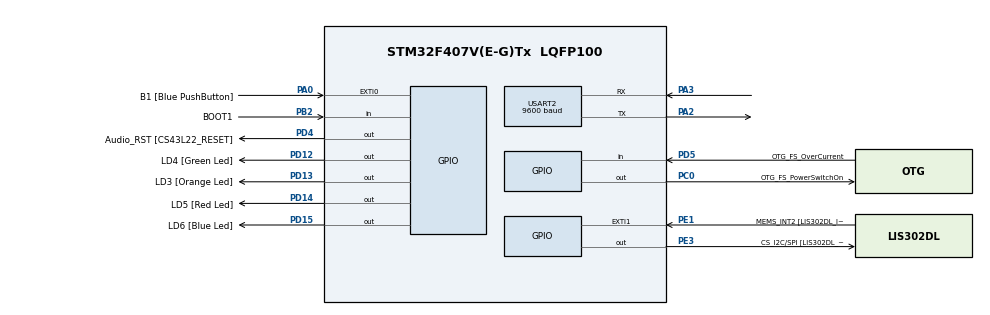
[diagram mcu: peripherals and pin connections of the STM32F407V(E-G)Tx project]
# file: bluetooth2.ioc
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Dma.Request0=USART2_RX
Dma.USART2_RX.0.Direction=DMA_PERIPH_TO_MEMORY
Dma.USART2_RX.0.FIFOMode=DMA_FIFOMODE_DISABLE
Dma.USART2_RX.0.Instance=DMA1_Stream5
Dma.USART2_RX.0.MemDataAlignment=DMA_MDATAALIGN_BYTE
Dma.USART2_RX.0.MemInc=DMA_MINC_ENABLE
Dma.USART2_RX.0.Mode=DMA_NORMAL
Dma.USART2_RX.0.PeriphDataAlignment=DMA_PDATAALIGN_BYTE
Dma.USART2_RX.0.PeriphInc=DMA_PINC_DISABLE
Dma.USART2_RX.0.Priority=DMA_PRIORITY_LOW
Mcu.Family=STM32F4
Mcu.Name=STM32F407V(E-G)Tx
Mcu.Package=LQFP100
NVIC.DMA1_Stream5_IRQn=true\:0\:0\:false\:false\:true\:false\:true
NVIC.PriorityGroup=NVIC_PRIORITYGROUP_0
PA0-WKUP.GPIO_Label=B1 [Blue PushButton]
PA0-WKUP.Signal=GPXTI0
PA10.GPIO_Label=OTG_FS_ID
PA10.GPIO_Mode=GPIO_MODE_AF_PP
PA10.GPIO_PuPd=GPIO_NOPULL
PA10.GPIO_Speed=GPIO_SPEED_FREQ_LOW
PA10.Signal=USB_OTG_FS_ID
PA11.GPIO_Label=OTG_FS_DM
PA11.GPIO_Mode=GPIO_MODE_AF_PP
PA11.GPIO_PuPd=GPIO_NOPULL
PA11.GPIO_Speed=GPIO_SPEED_FREQ_LOW
PA11.Signal=USB_OTG_FS_DM
PA12.GPIO_Label=OTG_FS_DP
PA12.GPIO_Mode=GPIO_MODE_AF_PP
PA12.GPIO_PuPd=GPIO_NOPULL
PA12.GPIO_Speed=GPIO_SPEED_FREQ_LOW
PA12.Signal=USB_OTG_FS_DP
PA13.GPIO_Label=SWDIO
PA13.Signal=SYS_JTMS-SWDIO
PA14.GPIO_Label=SWCLK
PA14.Signal=SYS_JTCK-SWCLK
PA2.Mode=Asynchronous
PA2.Signal=USART2_TX
PA3.Mode=Asynchronous
PA3.Signal=USART2_RX
PA4.GPIO_Label=I2S3_WS [CS43L22_LRCK]
PA4.GPIO_Mode=GPIO_MODE_AF_PP
PA4.GPIO_PuPd=GPIO_NOPULL
PA4.GPIO_Speed=GPIO_SPEED_FREQ_LOW
PA4.Signal=I2S3_WS
PA5.GPIO_Label=SPI1_SCK [LIS302DL_SCL/SPC]
PA5.GPIO_Mode=GPIO_MODE_AF_PP
PA5.GPIO_PuPd=GPIO_NOPULL
PA5.GPIO_Speed=GPIO_SPEED_FREQ_LOW
PA5.Signal=SPI1_SCK
PA6.GPIO_Label=SPI1_MISO [LIS302DL_SDO]
PA6.GPIO_Mode=GPIO_MODE_AF_PP
PA6.GPIO_PuPd=GPIO_NOPULL
PA6.GPIO_Speed=GPIO_SPEED_FREQ_LOW
PA6.Signal=SPI1_MISO
PA7.GPIO_Label=SPI1_MOSI [LIS302DL_SDA/SDI/SDO]
PA7.GPIO_Mode=GPIO_MODE_AF_PP
PA7.GPIO_PuPd=GPIO_NOPULL
PA7.GPIO_Speed=GPIO_SPEED_FREQ_LOW
PA7.Signal=SPI1_MOSI
PA9.GPIO_Label=VBUS_FS
PA9.GPIO_Mode=GPIO_MODE_INPUT
PA9.GPIO_PuPd=GPIO_NOPULL
PA9.Signal=USB_OTG_FS_VBUS
PB10.GPIO_Label=CLK_IN [MP45DT02_CLK]
PB10.GPIO_Mode=GPIO_MODE_AF_PP
PB10.GPIO_PuPd=GPIO_NOPULL
PB10.GPIO_Speed=GPIO_SPEED_FREQ_LOW
PB10.Signal=I2S2_CK
PB2.GPIO_Label=BOOT1
PB2.GPIO_Mode=GPIO_MODE_INPUT
PB2.GPIO_PuPd=GPIO_NOPULL
PB2.Signal=GPIO_Input
PB3.GPIO_Label=SWO
PB3.Signal=SYS_JTDO-SWO
PB6.GPIO_Label=Audio_SCL [CS43L22_SCL]
PB6.GPIO_Mode=GPIO_MODE_AF_OD
PB6.GPIO_PuPd=GPIO_NOPULL
PB6.GPIO_Speed=GPIO_SPEED_FREQ_LOW
PB6.Signal=I2C1_SCL
PB9.GPIO_Label=Audio_SDA [CS43L22_SDA]
PB9.GPIO_Mode=GPIO_MODE_AF_OD
PB9.GPIO_PuPd=GPIO_NOPULL
PB9.GPIO_Speed=GPIO_SPEED_FREQ_LOW
PB9.Signal=I2C1_SDA
PC0.GPIO_Label=OTG_FS_PowerSwitchOn
PC0.GPIO_PuPd=GPIO_NOPULL
PC0.GPIO_Speed=GPIO_SPEED_FREQ_LOW
PC0.PinState=GPIO_PIN_SET
PC0.Signal=GPIO_Output
PC10.GPIO_Label=I2S3_SCK [CS43L22_SCLK]
PC10.GPIO_Mode=GPIO_MODE_AF_PP
PC10.GPIO_PuPd=GPIO_NOPULL
PC10.GPIO_Speed=GPIO_SPEED_FREQ_LOW
PC10.Signal=I2S3_CK
PC12.GPIO_Label=I2S3_SD [CS43L22_SDIN]
PC12.GPIO_Mode=GPIO_MODE_AF_PP
PC12.GPIO_PuPd=GPIO_NOPULL
PC12.GPIO_Speed=GPIO_SPEED_FREQ_LOW
PC12.Signal=I2S3_SD
PC14-OSC32_IN.GPIO_Label=PC14-OSC32_IN
PC14-OSC32_IN.Signal=RCC_OSC32_IN
PC15-OSC32_OUT.GPIO_Label=PC15-OSC32_OUT
PC15-OSC32_OUT.Signal=RCC_OSC32_OUT
PC3.GPIO_Label=PDM_OUT [MP45DT02_DOUT]
PC3.GPIO_Mode=GPIO_MODE_AF_PP
PC3.GPIO_PuPd=GPIO_NOPULL
PC3.GPIO_Speed=GPIO_SPEED_FREQ_LOW
PC3.Signal=I2S2_SD
PC7.GPIO_Label=I2S3_MCK [CS43L22_MCLK]
PC7.GPIO_Mode=GPIO_MODE_AF_PP
PC7.GPIO_PuPd=GPIO_NOPULL
PC7.GPIO_Speed=GPIO_SPEED_FREQ_LOW
PC7.Signal=I2S3_MCK
PD12.GPIO_Label=LD4 [Green Led]
PD12.GPIO_PuPd=GPIO_NOPULL
PD12.GPIO_Speed=GPIO_SPEED_FREQ_LOW
PD12.Signal=GPIO_Output
PD13.GPIO_Label=LD3 [Orange Led]
PD13.GPIO_PuPd=GPIO_NOPULL
PD13.GPIO_Speed=GPIO_SPEED_FREQ_LOW
PD13.Signal=GPIO_Output
PD14.GPIO_Label=LD5 [Red Led]
PD14.GPIO_PuPd=GPIO_NOPULL
PD14.GPIO_Speed=GPIO_SPEED_FREQ_LOW
PD14.Signal=GPIO_Output
PD15.GPIO_Label=LD6 [Blue Led]
PD15.GPIO_PuPd=GPIO_NOPULL
PD15.GPIO_Speed=GPIO_SPEED_FREQ_LOW
PD15.Signal=GPIO_Output
PD4.GPIO_Label=Audio_RST [CS43L22_RESET]
PD4.GPIO_PuPd=GPIO_NOPULL
PD4.GPIO_Speed=GPIO_SPEED_FREQ_LOW
PD4.Signal=GPIO_Output
PD5.GPIO_Label=OTG_FS_OverCurrent
PD5.GPIO_Mode=GPIO_MODE_INPUT
PD5.GPIO_PuPd=GPIO_NOPULL
PD5.Signal=GPIO_Input
PE1.GPIO_Label=MEMS_INT2 [LIS302DL_INT2]
PE1.GPIO_ModeDefaultEXTI=GPIO_MODE_EVT_RISING
PE1.GPIO_PuPd=GPIO_NOPULL
PE1.Signal=GPXTI1
PE3.GPIO_Label=CS_I2C/SPI [LIS302DL_CS_I2C/SPI]
PE3.GPIO_PuPd=GPIO_NOPULL
PE3.GPIO_Speed=GPIO_SPEED_FREQ_LOW
PE3.Signal=GPIO_Output
PH0-OSC_IN.GPIO_Label=PH0-OSC_IN
PH0-OSC_IN.Signal=RCC_OSC_IN
PH1-OSC_OUT.GPIO_Label=PH1-OSC_OUT
PH1-OSC_OUT.Signal=RCC_OSC_OUT
ProjectManager.HeapSize=0x200
ProjectManager.StackSize=0x400
ProjectManager.TargetToolchain=Makefile
RCC.48MHZClocksFreq_Value=14285714.285714285
RCC.AHBFreq_Value=25000000
RCC.APB1CLKDivider=RCC_HCLK_DIV4
RCC.APB1Freq_Value=6250000
RCC.APB1TimFreq_Value=12500000
RCC.APB2CLKDivider=RCC_HCLK_DIV2
RCC.APB2Freq_Value=12500000
RCC.APB2TimFreq_Value=25000000
RCC.CortexFreq_Value=25000000
RCC.HCLKFreq_Value=25000000
RCC.HSE_VALUE=8000000
RCC.HSI_VALUE=16000000
RCC.LSE_VALUE=32768
RCC.PLLM=8
RCC.PLLN=50
RCC.PLLP=RCC_PLLP_DIV4
RCC.PLLQ=7
RCC.SYSCLKFreq_VALUE=25000000
RCC.SYSCLKSource=RCC_SYSCLKSOURCE_PLLCLK
RCC.VCOOutputFreq_Value=100000000
USART2.BaudRate=9600
USART2.VirtualMode=VM_ASYNC
board=STM32F407G-DISC1

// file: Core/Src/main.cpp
/* USER CODE BEGIN Header */
/**
  ******************************************************************************
  * @file           : main.c
  * @brief          : Main program body
  ******************************************************************************
  * @attention
  *
  * <h2><center>&copy; Copyright (c) 2021 STMicroelectronics.
  * All rights reserved.</center></h2>
  *
  * This software component is licensed by ST under BSD 3-Clause license,
  * the "License"; You may not use this file except in compliance with the
  * License. You may obtain a copy of the License at:
  *                        opensource.org/licenses/BSD-3-Clause
  *
  ******************************************************************************
  */
/* USER CODE END Header */
#include "main.h"

/* USER CODE BEGIN Includes */
#include <string.h>
#include <stdio.h>
#include <stdlib.h>

//Ben
#include "decisiontree.cpp"
#include <iostream>
#include <vector>
#include <string>
#include <cstring>
#include <fstream>
#include <cmath>
#include <map>
#include <algorithm>
using namespace std;

/* USER CODE END Includes */

UART_HandleTypeDef huart2;
DMA_HandleTypeDef hdma_usart2_rx;

//uint8_t buffer_rx[100];
char buffer_rx[100];

void SystemClock_Config(void);
static void MX_GPIO_Init(void);
static void MX_DMA_Init(void);
static void MX_USART2_UART_Init(void);

/* USER CODE BEGIN 0 */

void HAL_UART_RxCpltCallback(UART_HandleTypeDef *huart){

}

/* USER CODE END 0 */

  int send (char * txData){
  //
  int bytesToSend =10+strlen(txData);
  char send[10000];

  send[0]='#';

  //length of payload
  // Todo: maybe overflow an Bytes
  char msglen [11];
  sprintf(msglen,"%d",strlen(txData));

  int i =1;
  while (i<(strlen(msglen)+1)){
  send[i]=msglen[i-1];
  i=i+1;
  }
  send[i]='|';
  i=i+1;
  int sendi=0;
  while(sendi<strlen(txData)){
  send[i] = txData[sendi];
  i=i+1;
  sendi=sendi+1;
  }

  //Union length of payload and payload, send it
  //strcat (send, txData);

  HAL_UART_Transmit(&huart2, (uint8_t *)  send, strlen(send),400);
  return 1;

  }

  void receievCPP(char * arg){
  	char txData[100];
      while (1){
    	HAL_UART_Receive(&huart2,(uint8_t *) buffer_rx,1,1000);
    	if (buffer_rx[0]== (uint8_t) '#')
    		{
    		break;
    		}

    	}

    	//check for payload length
    	int j=0;
    	char msglen [8];
    	while (1){
    	HAL_UART_Receive(&huart2,(uint8_t *) buffer_rx,1,1000);
    	if (buffer_rx[0]== (uint8_t) '|')
    		{
    		break;
    		}
    	msglen[j]=buffer_rx[0];
    	j= j+1;
    	}

    	int msglength=0;
    	sscanf (msglen, "%d", &msglength);

    	//receive payload
    	HAL_UART_Receive(&huart2,(uint8_t *) buffer_rx,msglength,1000);

    	 int i =0;
    	while (i<msglength){
    	txData[i]= (uint8_t) buffer_rx[i];
    	//buffer_rx[i]=NULL;
    	i=i+1;
    	}

      	strcpy( arg,buffer_rx);
      }

  int receiev (char * txData){
  while (1){
	HAL_UART_Receive(&huart2,(uint8_t *) buffer_rx,1,1000);
	if (buffer_rx[0]== (uint8_t) '#')
		{
		break;
		}

	}

	//check for payload length
	int j=0;
	char msglen [8];
	while (1){
	HAL_UART_Receive(&huart2,(uint8_t *) buffer_rx,1,1000);
	if (buffer_rx[0]== (uint8_t) '|')
		{
		break;
		}
	msglen[j]=buffer_rx[0];
	j= j+1;
	}

	int msglength=0;
	sscanf (msglen, "%d", &msglength);

	//receive payload
	HAL_UART_Receive(&huart2,(uint8_t *) buffer_rx,msglength,1000);

	 int i =0;
	while (i<msglength){
	txData[i]=buffer_rx[i];
	buffer_rx[i]=NULL;
	i=i+1;
	}

  	return 1;
  }

  //Ben

/*  void SplitStringH(char* s, vector<char*> &v){

   	char* temp = "";
   	for(int i=0;i<strlen(s);++i){

   		if(s[i]=='#'){
   			v.push_back(temp);
   			temp = "";
   		}
   		else{
   			temp.push_back(s[i]);
   		}

   	}
   	v.push_back(temp);

   }

   void SplitStringD(char* s, vector<char*> &v){

     	char* temp = "";
     	for(int i=0;i<s.length();++i){

     		if(s[i]=='$'){
     			v.push_back(temp);
     			temp = "";
     		}
     		else{
     			temp.push_back(s[i]);
     		}

     	}
     	v.push_back(temp);

     }

   void SplitStringS(char* s, vector<char*> &v){

     	char* temp = "";
     	for(int i=0;i<s.length();++i){

     		if(s[i]=='/'){
     			v.push_back(temp);
     			temp = "";
     		}
     		else{
     			temp.push_back(s[i]);
     		}

     	}
     	v.push_back(temp);

     }*/

/*  Table StringToTable(char * s1){
 	  vector<string> input;

 	  //may be different depending on libraries
 	  //string slashString = str(s1);
 	  char* slashString(s1);

 	  SplitStringS(slashString,input);

 	  string attrName = input[0];
 	  string data = input[1];
 	  string attrValueList = input[2];

 	 vector<string> attrNamefinal;
 	 SplitStringH(attrName,attrNamefinal);

 	 vector<string> datafinal;
 	 SplitStringD(data,datafinal);

 	 vector<vector<string>> datafinalfinal;
 	 for(int i = 0; i< datafinal.size();i++){
 		 SplitStringH(datafinal[i],datafinalfinal[i]);
 	 }

 	 vector<string> attrValueListfinal;
 	 	 SplitStringD(attrValueList,attrValueListfinal);

 	 vector<vector<string>> attrValueListfinalfinal;
 	 for(int i = 0; i< attrValueListfinal.size();i++){
 	 	 SplitStringH(attrValueListfinal[i],attrValueListfinalfinal[i]);
 	 }

 	 Table tf;
 	       tf.attrName=attrNamefinal;
 	       tf.data=datafinalfinal;
 	       tf.attrValueList=attrValueListfinalfinal;

 	 return tf;
   }*/

  //Ben
  //Test kommentar

    void TableToString(Table t1, char * tableString){
 	  char attrName[1000]  = {};
 	  char data [1000] = {};
 	  char attrValueList [1000] = {};

 	  int attrNameSize = t1.attrName.size();

 	  for(int i = 0; i < attrNameSize; i++){
 		  if(i==0){

 			  sprintf(attrName, "%d", t1.attrName[0]);

 			  //attrName = '0'+ t1.attrName[0];
 		  }else{
 			  strcat(attrName,"#");

 			  char tmp [200];
 			  sprintf(tmp, "%d", t1.attrName[i]);
 			  strcat(attrName,tmp);

 		  }
 	  }

 	  for(int i = 0; i < t1.data.size(); i++){
 		  for(int a = 0; a < t1.data[i].size();a++){
 			  if(a == 0 && i==0){

 				  sprintf(data, "%d", t1.data[i][a]);

 				  //data.append(std::to_string(t1.data[i][a]));
 			  }else{

 				 strcat(data,"#");

 				 char tmp [200];
 				 sprintf(tmp, "%d", t1.data[i][a]);
 				 strcat(data,tmp);

 				  //data.append("#");
 				  //data.append(std::to_string(t1.data[i][a]));
 			  }
 		  }
 		  if(i != t1.data.size()-1){
 			  strcat(data,"$");
 			  //data.append("$");
 		  }
 	  }

 	  for(int i = 0; i < t1.attrValueList.size(); i++){
 	  		  for(int a = 0; a < t1.attrValueList[i].size();a++){
 	  			  if(a == 0 && i==0){
 	  				  sprintf(attrValueList, "%d", t1.attrValueList[i][a]);

 	  				 // data.append(std::to_string(t1.attrValueList[i][a]));
 	  			  }else{

 	  				  	strcat(attrValueList,"#");
 	  					char tmp [200];
 	  					sprintf(tmp, "%d", t1.attrValueList[i][a]);
 	  					strcat(attrValueList,tmp);

 	  				  //data.append("#");
 	  				  //data.append(std::to_string(t1.attrValueList[i][a]));
 	  			  }
 	  		  }
 	  		  if(i != t1.attrValueList.size()-1){
 	  			  strcat(attrValueList,"$");
 	  			  //data.append("$");
 	  		  }
 	  	  }

 	 strcpy (tableString, attrName);
 	 strcat(tableString,"/#");
 	  strcat(tableString,data);
 	 strcat(tableString,"/");
 	  strcat(tableString,attrValueList);
 	/*  final.append("/");
 	  final.append(data);
 	  final.append("/");
 	  final.append(attrValueList);*/

 	  //Char* c = const_cast<char*>(final.c_str());

   }

//interne trennung # - extern $

int main(void)
{

  /* MCU Configuration--------------------------------------------------------*/

  /* Reset of all peripherals, Initializes the Flash interface and the Systick. */
  HAL_Init();

  /* Configure the system clock */
  SystemClock_Config();

  /* Initialize all configured peripherals */
  MX_GPIO_Init();
  //MX_DMA_Init();
  MX_USART2_UART_Init();
  /* USER CODE BEGIN 2 */

  //Ben
    /* USER CODE BEGIN 2 */

        vector<int> attrName;
        vector<vector<int> > data;

        vector<vector<int> > attrValueList;

        //examples - need to be adjusted
        attrName = {1,2};
        data ={{0, 60, 402, 19, 0, 2, 2, 13, 0}, {0, 70, 402, 44, 0, 1, 2, 13, 0}, {1, 50, 402, 34, 0, 3, 1, 14, 0}, {0, 60, 402, 24, 0, 1, 1, 14, 0}, {0, 60, 402, 14, 0, 1, 1, 14, 0}, {0, 50, 403, 29, 0, 2, 2, 24, 0}, {1, 40, 403, 19, 1, 3, 2, 13, 0}, {0, 60, 402, 14, 0, 2, 1, 14, 0}, {0, 60, 402, 49, 1, 3, 1, 5, 0}, {0, 50, 402, 14, 0, 1, 1, 13, 0}, {0, 30, 403, 34, 0, 2, 1, 13, 0}, {0, 40, 403, 14, 0, 2, 2, 14, 0}, {0, 60, 402, 24, 0, 2, 2, 13, 0}, {0, 50, 403, 34, 0, 3, 1, 14, 0}, {1, 60, 402, 34, 1, 2, 2, 23, 1}, {1, 50, 403, 34, 0, 3, 1, 23, 0}, {0, 50, 403, 14, 0, 1, 1, 14, 0}, {0, 50, 402, 19, 1, 2, 1, 5, 1}, {0, 50, 402, 29, 1, 3, 2, 13, 0}, {0, 40, 403, 29, 0, 2, 2, 5, 0}, {0, 40, 403, 4, 0, 3, 1, 5, 0}, {0, 40, 403, 29, 999, 2, 1, 24, 1}, {1, 40, 403, 34, 1, 3, 1, 13, 1}, {0, 60, 402, 19, 0, 2, 1, 14, 0}, {0, 50, 401, 19, 0, 2, 1, 14, 0}, {1, 40, 403, 29, 0, 2, 1, 14, 1}, {0, 40, 403, 24, 0, 2, 1, 5, 0}, {0, 50, 402, 24, 0, 3, 1, 13, 0}, {1, 60, 402, 34, 0, 3, 2, 5, 0}, {1, 40, 403, 34, 0, 2, 2, 13, 0}, {1, 40, 403, 29, 0, 3, 1, 13, 0}, {0, 60, 402, 34, 0, 2, 1, 14, 1}, {0, 60, 402, 29, 0, 3, 2, 13, 0},
        		{0, 50, 403, 39, 0, 2, 2, 13, 0},
				{0, 40, 403, 34, 0, 2, 1, 24, 0},
				{0, 30, 403, 29, 1, 2, 2, 13, 1}
        };

        Table table;
        table.attrName=attrName;
        table.data=data;
        table.attrValueList=attrValueList;

        //initializing the DecisionTree
        DecisionTree decTree(table) ;

        //Observation table
        vector<int> obsattrName;
        vector<vector<int> > obsdata;

        vector<vector<int> > obsattrValueList;

        //example - needs to get filled with the data that is received
        obsattrName = {1,2,3,4};
        obsdata = {{0,1,0,0},
          		   {1,0,1,1},
          		   {0,0,0,0}};

        Table obstable;
        obstable.attrName=obsattrName;
        obstable.data=obsdata;
        obstable.attrValueList=obsattrValueList;

        Table res;
        res.attrName=attrName;

        //This bool will decide whether the drone is the master drone
        bool master = false;
  /* USER CODE END 2 */

  /* Infinite loop */
  while (1)
  {

	        /* USER CODE BEGIN 3 */

	    	  //Classification

	    	  for(int i=0;i < obstable.data.size(); i++) {
	    	  		vector<int> result = obstable.data[i];
	    	  		result.push_back(decTree.guess(obstable.data[i]));
	    	  		res.data.push_back(result);
	    	  	}

	    	  //Send results of classification to master
	    	  if(!master){
	    		  char  a[10000];
	    		  TableToString(table, a);

	    		  bool equalsRequestCharacter=true;
	    		  	 while (1){
	    		  		char txData[100];
	    		  		receievCPP(txData);
	    		  		 //send(txData);

	    		  		equalsRequestCharacter =true;
	    		  		char right[]="/sent";
	    		  		int i;
	    		  		for (i=0;i<4;i++){
	    		  			if (txData[i]!=right[i]){
	    		  				equalsRequestCharacter=false;
	    		  				break;
	    		  			}
	    		  		}
	    		  		if (equalsRequestCharacter){
	    		  			break;
	    		  		}
	    		  	}

	    		  send(a);

	    	  }

	    	  //Wait

	    	  vector<int> h = res.data[0];
	    	  //vector<int> z = h[0];
	    	  int j = h[4];
	    	  int r = 55;
	    	  vector<int> h1 = res.data[1];
	    	  int f = h1[4];
			  vector<int> h2 = res.data[2];
			  int roh = h2[4];
			  vector<int> h3 = res.data[3];
	          int dah = h3[4];

	    	  //Master-drone needs to aggregate
	    	  if(master){
	    		  vector<Table> reses;
	    		  char * a;
	    		  //für einen wert, muss erweiter werden durch for loop um mehrere empfangen zu können

	    		  char * c1;
	    		  //receiev(c1);
	    		 // reses[0] = StringToTable(c1);

	    		  vector<int> mod;
	    		  vector<int> different_results;
	    		  for(int i=0; reses[0].data.size();i++){
	    			for(int x =0; reses.size();x++){

	    				int r1 = reses[x].data[i].back();
	    				auto it = std::find(different_results.begin(), different_results.end(),r1);

	    				if(it!=different_results.end()){
	    					mod[std::distance(different_results.begin(),it)]++;
	    				}else{
	    					different_results.push_back(r1);
	    					mod.push_back(1);
	    				}
	    			}
	    		  }
	    		  //Find mode in mod
	    		  int endresult;
	    		  endresult= *max_element(mod.begin(),mod.end());

	    		  //Send endresult (optional weights for federated learning)
	    		  send((char *) endresult);
	    		 // send(endresult);
	    	  }

	    	  //Receive endresult - For future projects

	    	  //recData();
	    	  if(!master){
	    		  char * a;
	    		  receiev(a);
	    		  int z = (int) a;
	    	  }
  }
  /* USER CODE END 3 */
}

void SystemClock_Config(void)
{
  RCC_OscInitTypeDef RCC_OscInitStruct = {0};
  RCC_ClkInitTypeDef RCC_ClkInitStruct = {0};

  /** Configure the main internal regulator output voltage
  */
  __HAL_RCC_PWR_CLK_ENABLE();
  __HAL_PWR_VOLTAGESCALING_CONFIG(PWR_REGULATOR_VOLTAGE_SCALE1);
  /** Initializes the RCC Oscillators according to the specified parameters
  * in the RCC_OscInitTypeDef structure.
  */
  RCC_OscInitStruct.OscillatorType = RCC_OSCILLATORTYPE_HSI;
  RCC_OscInitStruct.HSIState = RCC_HSI_ON;
  RCC_OscInitStruct.HSICalibrationValue = RCC_HSICALIBRATION_DEFAULT;
  RCC_OscInitStruct.PLL.PLLState = RCC_PLL_NONE;
  if (HAL_RCC_OscConfig(&RCC_OscInitStruct) != HAL_OK)
  {
    Error_Handler();
  }
  /** Initializes the CPU, AHB and APB buses clocks
  */
  RCC_ClkInitStruct.ClockType = RCC_CLOCKTYPE_HCLK|RCC_CLOCKTYPE_SYSCLK
                              |RCC_CLOCKTYPE_PCLK1|RCC_CLOCKTYPE_PCLK2;
  RCC_ClkInitStruct.SYSCLKSource = RCC_SYSCLKSOURCE_HSI;
  RCC_ClkInitStruct.AHBCLKDivider = RCC_SYSCLK_DIV1;
  RCC_ClkInitStruct.APB1CLKDivider = RCC_HCLK_DIV1;
  RCC_ClkInitStruct.APB2CLKDivider = RCC_HCLK_DIV1;

  if (HAL_RCC_ClockConfig(&RCC_ClkInitStruct, FLASH_LATENCY_0) != HAL_OK)
  {
    Error_Handler();
  }
}

static void MX_USART2_UART_Init(void)
{

  huart2.Instance = USART2;
  huart2.Init.BaudRate = 38400;
  huart2.Init.WordLength = UART_WORDLENGTH_8B;
  huart2.Init.StopBits = UART_STOPBITS_1;
  huart2.Init.Parity = UART_PARITY_NONE;
  huart2.Init.Mode = UART_MODE_TX_RX;
  huart2.Init.HwFlowCtl = UART_HWCONTROL_NONE;
  huart2.Init.OverSampling = UART_OVERSAMPLING_16;
  if (HAL_UART_Init(&huart2) != HAL_OK)
  {
    Error_Handler();
  }

}

static void MX_GPIO_Init(void)
{
  GPIO_InitTypeDef GPIO_InitStruct = {0};

  /* GPIO Ports Clock Enable */
  __HAL_RCC_GPIOA_CLK_ENABLE();
  __HAL_RCC_GPIOD_CLK_ENABLE();

  /*Configure GPIO pin Output Level */

  /*Configure GPIO pins : LD12_Pin LD13_Pin LD14_Pin LD15_Pin */

  GPIO_InitStruct.Mode = GPIO_MODE_OUTPUT_PP;
  GPIO_InitStruct.Pull = GPIO_NOPULL;
  GPIO_InitStruct.Speed = GPIO_SPEED_FREQ_LOW;
  HAL_GPIO_Init(GPIOD, &GPIO_InitStruct);

}

void Error_Handler(void)
{
  __disable_irq();
  while (1)
  {
  }
}

/************************ (C) COPYRIGHT STMicroelectronics *****END OF FILE****/
